VERSION 5.8 ; UNITS DATABASE MICRONS 1000 ; END UNITS
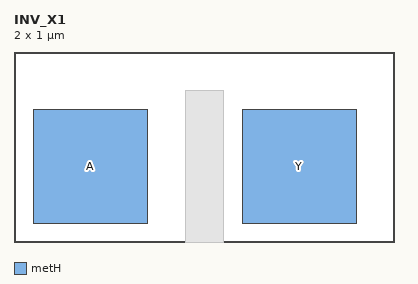
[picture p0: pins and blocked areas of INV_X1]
MACRO INV_X1 CLASS CORE ; SIZE 2 BY 1 ; SYMMETRY X Y R90 ; SITE unit ;
  PIN Y DIRECTION OUTPUT ; USE SIGNAL ; PORT LAYER metH ; RECT 1.2 0.1 1.8 0.7 ; END END Y
  PIN A DIRECTION INPUT ; USE SIGNAL ; PORT LAYER metH ; RECT 0.1 0.1 0.7 0.7 ; END END A
  OBS LAYER metH ; RECT 0.9 0 1.1 0.8 ; END
END INV_X1 END LIBRARY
